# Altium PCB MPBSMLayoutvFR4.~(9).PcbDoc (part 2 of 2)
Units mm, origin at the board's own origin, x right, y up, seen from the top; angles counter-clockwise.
Board outline 131.7 x 110.39 mm, 4 copper layers (Top Layer, Power, GroundPlane, Bottom Layer), stack 2.286 mm thick; 156 components, 77 nets, 429 pads, 117 vias.
Unrouted connection lines stored in the file: 44.

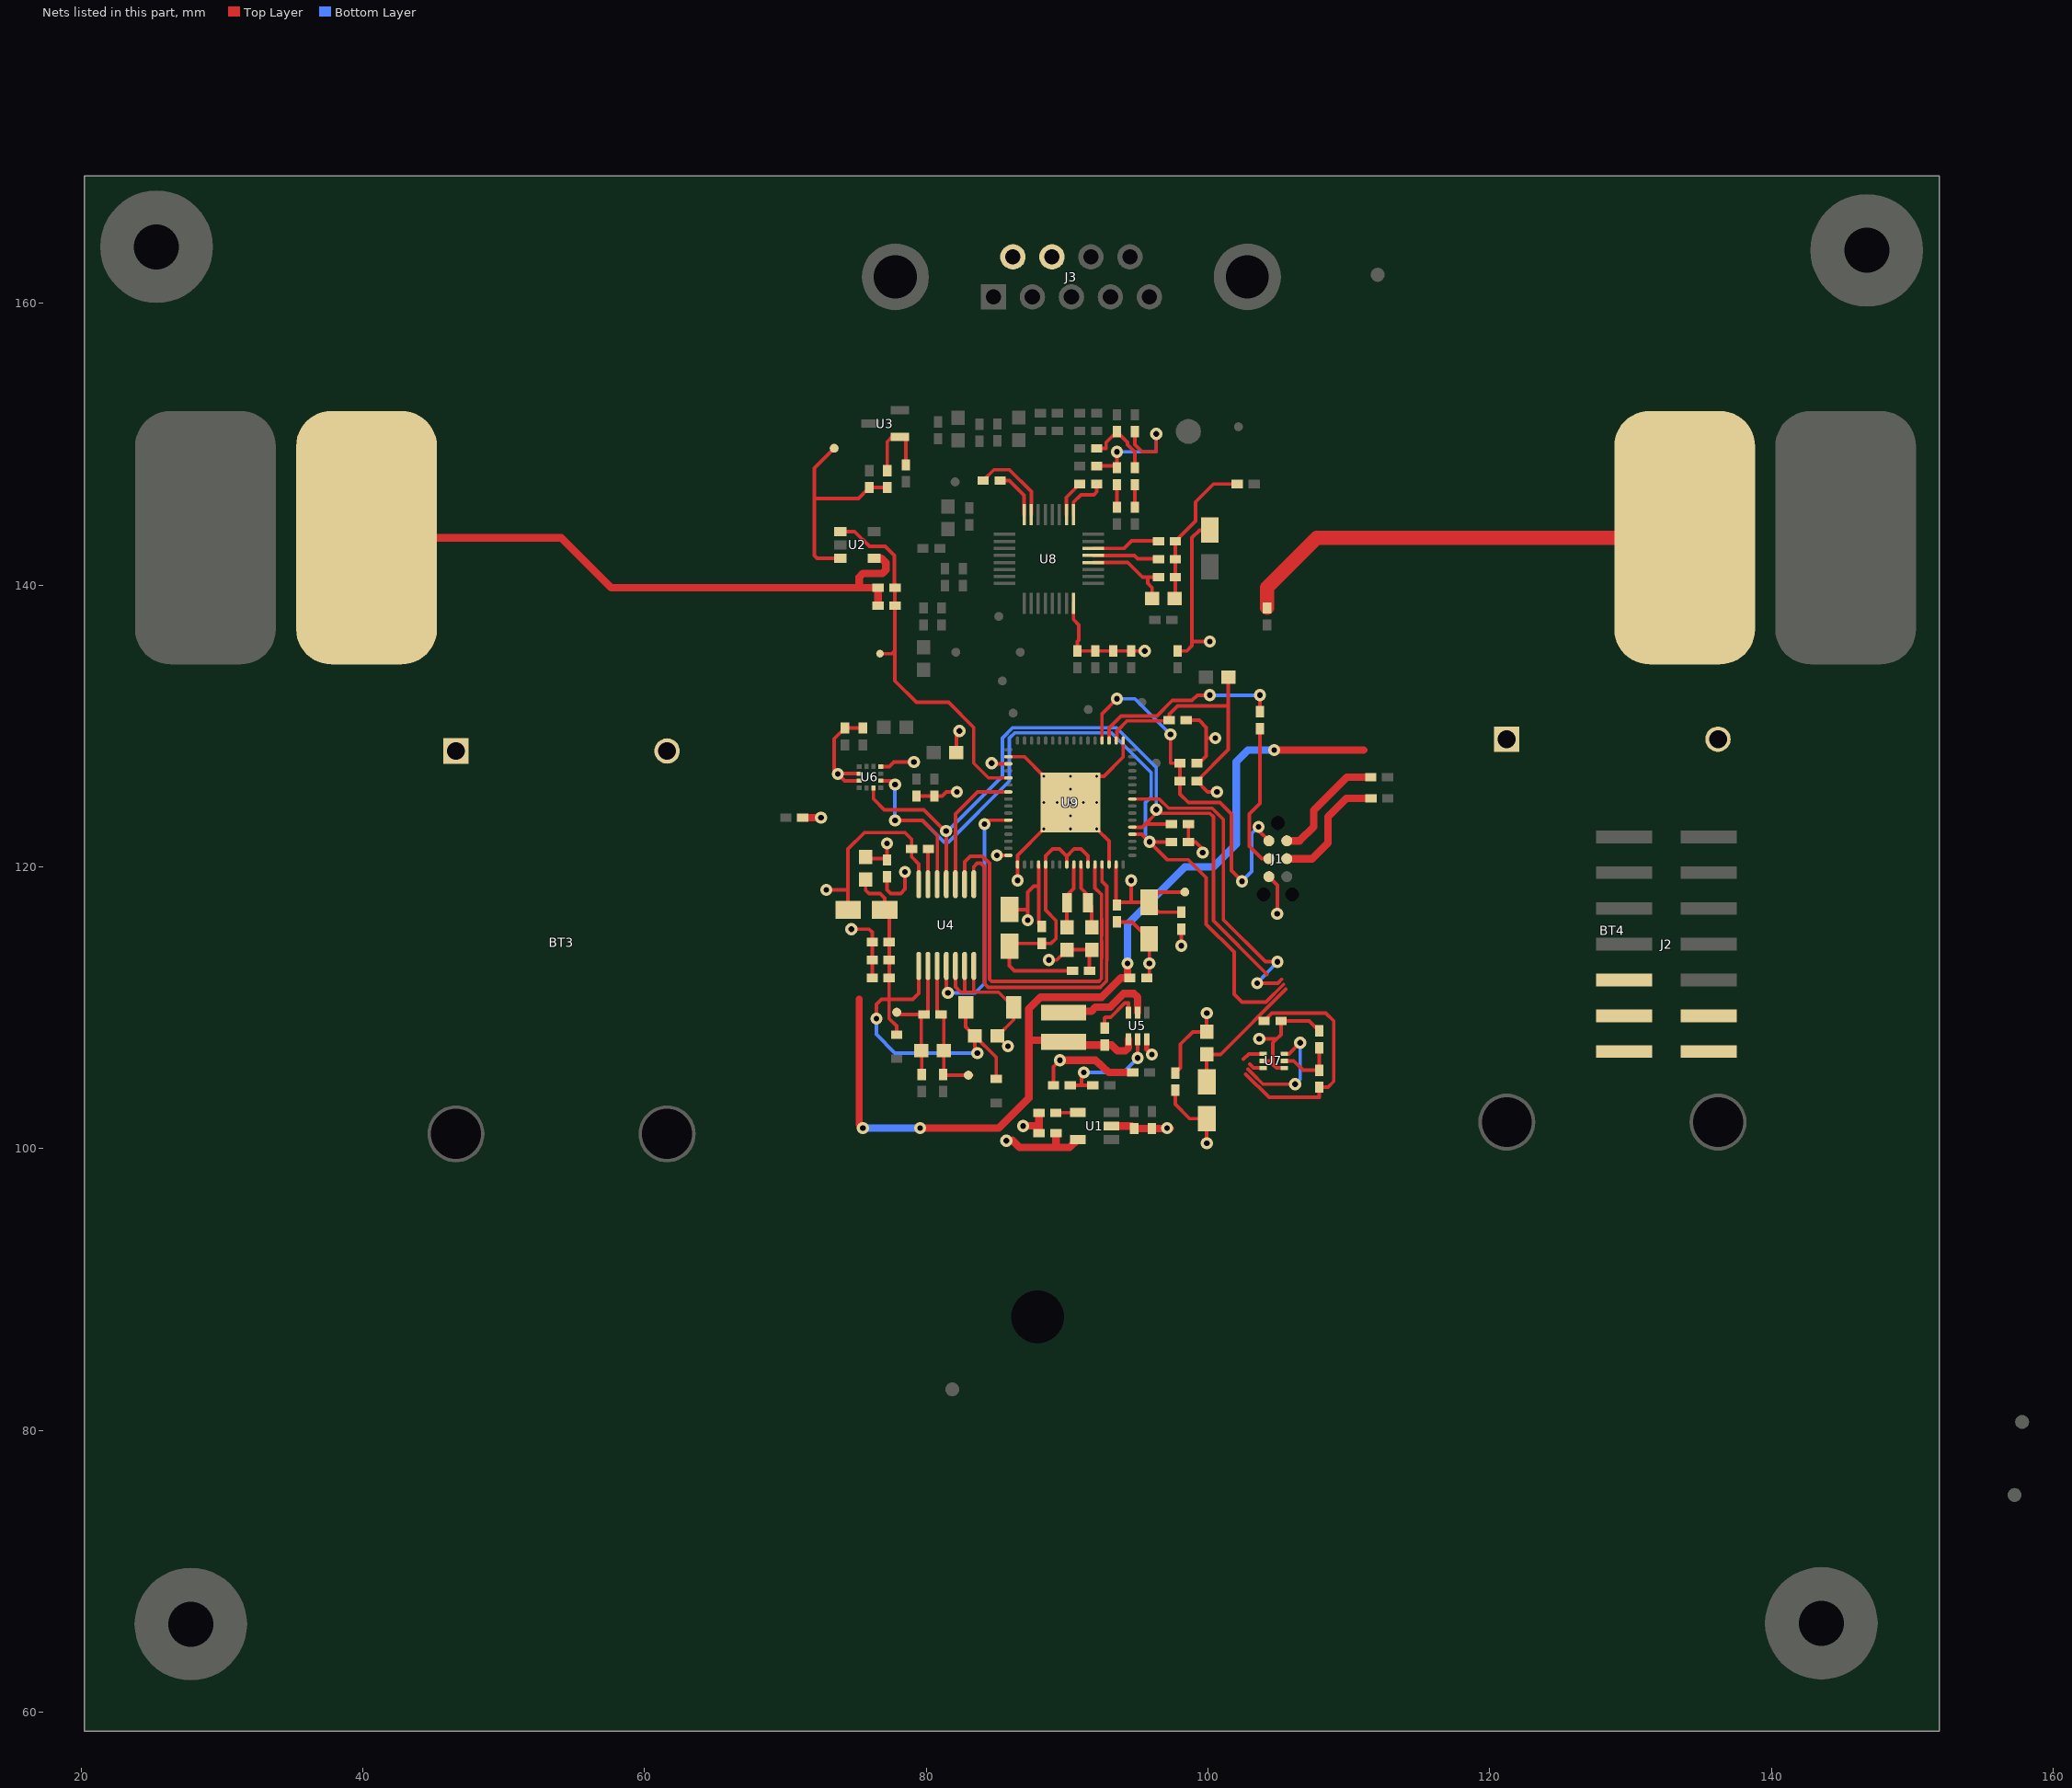
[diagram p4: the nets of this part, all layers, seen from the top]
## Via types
v1: diameter 0.864, hole 0.406, Top Layer to Bottom Layer, 104 vias
v2: diameter 0.5, hole 0.2, Top Layer to Bottom Layer, 13 vias

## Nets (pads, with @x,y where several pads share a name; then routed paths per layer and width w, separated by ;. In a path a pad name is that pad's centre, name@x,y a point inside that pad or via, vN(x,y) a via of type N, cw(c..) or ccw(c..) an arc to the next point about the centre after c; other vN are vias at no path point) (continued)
BOOST_INPUT: BT3.1 BT4.1 C34.1 L7.1 R16.1 U5.1 | length 73.3
  Top Layer w0.254: L7.1@89.739,107.681 L7.1@89.748,107.672 ; v1(94.285,113.132) v1@94.447,112.97
  Top Layer w0.5: 75.235,110.592 75.235,101.702 v1(75.489,101.448)
  Top Layer w0.54: v1(79.553,101.448) 85.141,101.448 87.274,103.581 87.274,109.906 88.113,110.744 92.456,110.744 93.828,112.116 C34.1@94.447,112.116 ; 87.274,107.696 L7.1@89.739,107.681 ; L7.1@89.959,107.35 R16.1@92.659,107.35 93.145,107.35 93.561,106.934 94.132,106.934 94.346,107.148 U5.1@94.346,107.762 ; C34.1@94.285,112.278 v1(94.285,113.132) ; v1(104.699,128.287) 111.048,128.287
  Bottom Layer w0.54: v1(75.489,101.448) v1(79.553,101.448) ; v1(94.285,113.132) 94.285,115.926 98.349,119.99 100.381,119.99 101.997,121.606 101.997,127.448 102.836,128.287 v1(104.699,128.287)
DVCC: 1.1 C1.1 C5.1 C6.1 C10.1 C14.1 C18.1 L1.1 L2.1 L3.1 L5.1 R1.1 R6.2 R31.1 R32.1 U1.5 U9.18 U9.35 U9.48 U9.63 | length 53
  Top Layer w0.254: L1.1@75.489,120.59 77.067,120.59 C10.1@77.091,120.613 ; C10.1@77.216,120.488 v1(77.216,121.666) ; L3.1@82.131,128.118 82.131,129.426 v1(82.347,129.642) ; v1@84.677,127.312 U9.35@85.821,127.312 ; v1(85.003,120.812) U9.48@85.821,120.812 ; U9.63@93.472,120.162 93.472,117.339 C6.1@93.523,117.288 ; U9.18@93.472,128.962 93.518,129.008 93.518,129.637 94.237,130.356 97.193,130.356 C18.1@97.241,130.404 97.241,130.82 97.841,131.42 101.397,131.42 ; C6.1@93.715,117.48 C1.1@95.809,117.48 ; 94.542,117.483 v1(94.542,119.027) ; C14.1@97.665,105.35 98.044,105.728 98.044,107.414 98.915,108.286 L2.1@99.906,108.286 v1(99.906,109.621) ; R1.1@98.095,116.78 96.509,116.78 C1.1@95.809,117.48 ; 1.1@98.349,118.212 96.541,118.212 C1.1@95.809,117.48 ; R32.1@98.603,123.038 R31.1@98.603,121.768 99.111,121.768 99.619,121.26 v1(99.619,121.006) ; v1(100.635,125.324) 99.965,125.324 R6.2@99.203,126.086 101.435,128.318 L5.1@101.435,133.452
  Top Layer w0.54: v1(85.674,100.559) v1@86.081,100.559 ; 86.106,100.584 86.614,100.076 89.2,100.076 ; C5.1@89.2,101.092 89.2,100.076 ; U1.5@90.748,100.65 90.174,100.076 89.2,100.076
  other v1: 84.633,127.356
EL_GSR1: C26.2 J3.7 R10.1 TP2.1 U2.4 | length 43.3
  Top Layer w0.254: U2.4@76.297,141.9 76.809,141.9
  Top Layer w0.54: TP2.1@40.259,143.358 54.077,143.358 57.633,139.802 R10.1@76.575,139.802 C26.2@76.575,138.532 ; 75.235,139.852 75.235,140.564 75.489,140.818 76.875,140.818 77.129,141.072 77.129,141.58 76.809,141.9
EL_GSR2: J3.6 R9.2 TP1.1 | length 32.6
  Top Layer w1: R9.2@104.191,138.37 104.191,139.827 107.721,143.358 TP1.1@133.833,143.358
GND: BT3.2 BT4.2 C1.2 C3.2 C4.2 C5.2 C6.2 C8.2 C9.2 C10.2 C11.2 C12.2 C13.2 C14.2 C15.2 C16.2 C17.2 C18.2 C19.2 C20.2 C21.2 C25.2 C27.2 C28.2 C29.1 C32.2 C33.2 C34.2 C35.2 C36.2 C37.2 C38.2 C41.2 C42.2 C58.2 C59.2 J1.6 J2.6 R2.1 R3.1 R17.1 U1.2 U4.5 U4.6 U4.7 U4.14 U5.3 U6.4 U6.8 U6.9 U7.2 U7.4 U8.24 U9.17 U9.34 U9.49 U9.62 U9.65 | length 145.9
  Top Layer w0.254: v1(72.898,118.364) 74.443,118.364 ; C9.2@74.443,116.942 74.443,118.364 ; v1(74.676,115.57) 75.946,115.57 76.159,115.357 C27.2@76.159,114.656 C11.2@76.159,113.386 C28.2@76.159,112.116 ; U6.9@75.222,126.111 74.194,126.111 v1(73.711,126.594) ; U6.8@75.222,126.611 73.728,126.611 v1(73.711,126.594) ; C37.2@75.489,129.847 C16.2@74.219,129.847 73.457,129.085 73.457,126.848 v1(73.711,126.594) ; U6.4@76.772,127.111 77.376,127.111 77.698,127.433 v1(79.117,127.433) ; C10.2@77.216,119.288 77.216,118.364 77.47,118.11 78.174,118.11 78.486,118.422 v1(78.486,119.634) ; C36.2@79.299,125.024 C17.2@80.569,125.024 81.124,125.024 81.424,125.324 v1(82.169,125.324) ; U4.14@79.464,118.764 79.464,120.193 78.953,120.704 C29.1@78.953,121.26 78.953,121.961 78.486,122.428 75.611,122.428 74.443,121.26 74.443,118.364 ; U4.5@82.064,112.964 82.064,111.484 82.448,111.1 83.363,111.1 ; 82.714,111.137 U4.6@82.714,112.964 ; U4.7@83.364,112.964 83.363,111.1 ; v1(85.797,107.266) 85.772,107.266 C33.2@85.047,107.991 86.201,109.145 C32.2@86.201,110.023 85.124,111.1 83.363,111.1 ; U9.34@85.821,127.812 86.971,127.812 v2(88.346,126.437) v2(90.221,124.562) ; v1(86.47,119.033) U9.49@86.47,120.162 86.47,120.811 v2(88.346,122.687) v2(90.221,124.562) ; v1(86.868,101.6) v1@86.881,101.613 ; v1(88.697,113.386) 89.243,113.386 89.967,114.11 C58.2@91.745,114.11 ; R17.1@89.021,104.496 89.021,105.812 v1(89.483,106.274) ; U8.24@90.447,138.704 90.447,137.544 90.829,137.162 90.829,136.099 90.729,135.999 C42.2@90.729,135.322 C41.2@91.999,135.322 C19.2@93.269,135.322 C20.2@94.539,135.322 v1@95.444,135.322 ; R2.1@91.583,112.624 C58.2@91.583,113.948 ; U9.62@92.971,120.162 92.971,121.811 v2(92.096,122.687) v2(90.221,124.562) ; C6.2@93.523,115.888 C6.2@93.523,116.088 94.601,116.088 C1.2@95.809,114.88 95.827,114.861 v1(95.827,113.132) 95.827,112.296 C34.2@95.647,112.116 C34.2@95.809,111.954 ; U9.17@93.972,128.962 93.972,127.805 92.604,126.437 v2(92.096,126.437) v2(90.221,124.562) ; C3.2@94.574,101.6 C3.2@94.747,101.428 ; v1(97.079,101.448) 97.079,101.194 v1@97.313,101.428 ; C14.2@97.665,104.15 97.665,103.147 98.691,102.122 C12.2@99.906,102.122 v1(99.906,100.374) ; C21.2@97.841,135.322 98.492,135.322 98.857,135.687 98.857,143.358 99.395,143.896 C15.2@100.127,143.896 C15.2@100.127,144.374 ; C18.2@98.441,130.404 99.365,130.404 99.873,129.896 99.873,129.134 ; 98.857,135.992 v1(100.127,135.992) ; C25.2@99.203,127.356 99.365,127.356 99.873,127.864 99.873,129.134 ; v1(100.508,129.134) 99.873,129.134 ; v1(103.627,107.783) 104.872,107.783 ; U7.2@103.906,106.221 104.576,106.221 ; J1.6@104.318,119.304 104.927,118.694 104.927,116.688 v1(104.902,116.662) ; U7.4@105.406,105.721 104.851,105.721 104.601,105.971 104.601,107.512 104.872,107.783 ; C38.2@107.884,108.352 107.168,109.068 C13.2@105.182,109.068 105.182,108.093 104.872,107.783
  Top Layer w0.354: U5.3@95.646,107.762 95.646,107.046 v1(96.012,106.68)
  Top Layer w0.54: R3.1@71.221,123.489 v1(72.524,123.489) ; v1@86.881,101.613 88,101.613 ; C5.2@88,101.092 88,101.613 ; C8.2@88,102.54 88,101.613 ; v1(89.483,106.274) 90.799,106.274 91.999,106.274 92.964,105.41 C35.2@94.7,105.41 ; U1.2@93.148,101.6 C3.2@94.574,101.6 ; C3.2@94.747,101.428 C4.2@96.017,101.428 v1@97.313,101.428
  other v1: 95.504,135.322
  other v2: 90.221,122.687 90.221,123.624 88.346,124.562 89.283,124.562 91.158,124.562 92.096,124.562 90.221,125.499 90.221,126.437
GSR_ANALOG_OUTPUT: 2.1 C26.1 R10.2 U2.1 U9.37 | length 26.9
  Top Layer w0.254: U2.1@73.897,143.8 74.903,143.8 75.955,142.748 77.072,142.748 77.733,142.088 77.733,140.14 77.775,140.098 R10.2@77.775,139.802 C26.1@77.775,138.532 77.775,135.23 ; 2.1@76.708,135.128 77.673,135.128 ; 77.673,135.23 77.775,135.23 ; U9.37@85.821,126.312 84.407,126.312 83.363,127.356 83.363,129.896 81.585,131.674 79.299,131.674 77.775,133.198 77.775,135.23
JTAG_TCK: J1.4 J2.4 R7.1 | length 10.4
  Top Layer w0.254: R7.1@103.683,129.804 103.683,124.511 102.921,123.749 102.921,121.463 103.81,120.574 J1.4@104.318,120.574
JTAG_TDO/TDI: C25.1 J1.2 J2.2 R6.1 U9.20 | length 28.1
  Top Layer w0.254: U9.20@92.471,128.962 92.471,130.876 v1(93.523,131.928) ; v1(97.333,129.388) 97.333,127.356 C25.1@98.003,127.356 R6.1@98.003,126.086 98.003,125.162 98.603,124.562 100.829,124.562 101.651,123.74 101.651,119.736 v1(102.413,118.974) ; v1(103.581,122.843) 103.581,122.58 J1.2@104.318,121.844
  Bottom Layer w0.254: v1(93.523,131.928) 94.793,131.928 v1(97.333,129.388) ; v1(102.413,118.974) 103.099,119.659 103.099,122.36 v1(103.581,122.843)
JTAG_TEST/SBWTCK: R7.2 U9.19 | length 13.7
  Top Layer w0.254: U9.19@92.971,128.962 92.971,129.852 93.829,130.71 96.369,130.71 97.46,131.801 98.855,131.801 99.236,132.182 v1(100.127,132.182) ; R7.2@103.683,131.004 v1(103.683,132.182)
  Bottom Layer w0.254: v1(100.127,132.182) v1(103.683,132.182)
JTAG_VCC_TARGET_IN: J1.3 J2.3 R5.1 | length 8.8
  Top Layer w0.54: J1.3@105.588,120.574 107.391,120.574 108.509,121.691 108.509,122.707 108.509,123.546 109.824,124.861 R5.1@111.56,124.861
JTAG_VCC_TOOL_OUT: J1.1 J2.1 R4.1 | length 8.5
  Top Layer w0.54: J1.1@105.588,121.844 106.502,121.844 107.493,122.834 107.493,124.003 109.855,126.365 R4.1@111.541,126.365
MSP_AVCC: C2.1 C7.1 R1.2 U9.52 | length 9.3
  Top Layer w0.254: C2.1@86.222,116.972 87.203,116.972 ; v1(87.203,116.21) 87.203,116.972 ; C7.1@87.97,115.982 87.97,118.618 ; U9.52@87.97,120.162 87.97,118.618 ; v1(98.095,114.402) R1.2@98.095,115.58 ; 87.203,116.972 87.203,118.191 87.63,118.618 87.97,118.618
MSP_AVSS: C2.2 C7.2 R2.2 U9.53 U9.56 U9.59 | length 20.5
  Top Layer w0.254: C2.2@85.903,114.372 85.903,112.979 86.258,112.624 R2.2@90.383,112.624 ; C2.2@86.095,114.564 C7.2@88.189,114.564 88.859,114.564 89.205,114.91 89.205,116.18 88.47,116.914 U9.53@88.47,120.162 88.47,120.779 88.951,121.26 89.459,121.26 89.963,120.756 ; U9.56@89.971,120.162 89.971,120.756 90.475,121.26 90.983,121.26 91.471,120.771 U9.59@91.471,120.162
MSP_LFXIN: C59.1 U9.57 Y1.1 | length 4.1
  Top Layer w0.254: C59.1@89.967,115.71 89.967,117.438 Y1.1@89.979,117.45 ; Y1.1@89.979,117.97 90.471,118.462 U9.57@90.471,120.162
MSP_LFXOUT: C58.1 U9.58 Y1.2 | length 4.3
  Top Layer w0.254: U9.58@90.971,120.162 90.971,118.477 Y1.2@91.479,117.97 ; Y1.2@91.479,117.45 91.745,117.184 C58.1@91.745,115.71
MSP_P1.0_INT: U4.10 U9.39 | length 9.4
  Top Layer w0.254: U4.10@82.064,118.764 82.064,123.749 ; 82.079,123.749 83.642,125.312 U9.39@85.821,125.312
MSP_P2.7_INT: U7.3 U9.9 | length 24.2
  Top Layer w0.254: U9.9@94.621,124.812 96.544,124.812 97.202,124.154 100.281,124.154 101.089,123.346 101.089,116.234 104.064,113.259 v1(104.927,113.259) ; 102.968,105.989 103.236,105.721 U7.3@103.906,105.721 ; v1@103.488,111.743 104.949,111.743 105.217,112.011
  Bottom Layer w0.254: v1(103.48,111.735) v1(104.927,113.259)
MSP_P4.0_INT: U4.9 U9.60 | length 28.4
  Top Layer w0.254: U4.9@82.714,118.764 82.714,120.356 83.109,120.752 83.976,120.752 84.479,120.248 84.479,112.016 84.633,111.862 92.253,111.862 92.437,112.046 92.437,113.506 92.447,113.516 92.447,114.704 92.437,114.713 92.437,115.106 92.447,115.116 92.447,116.304 92.437,116.313 92.437,118.027 91.971,118.493 U9.60@91.971,120.162
MSP_P4.1_INT: U4.8 U9.61 | length 27.8
  Top Layer w0.254: U4.8@83.364,118.764 83.364,119.99 83.617,120.244 83.871,120.244 84.125,119.99 84.125,111.718 84.389,111.454 92.353,111.454 ; 92.353,111.461 92.791,111.9 92.791,113.36 92.801,113.369 92.801,118.612 92.471,118.942 U9.61@92.471,120.162
MSP_P9.3_OUT: U4.4 U9.43 | length 18
  Top Layer w0.254: U4.4@81.414,112.964 81.414,111.169 v1(81.534,111.049) ; v1(84.125,123.038) 84.399,123.312 U9.43@85.821,123.312
  Bottom Layer w0.254: v1(81.534,111.049) 83.456,111.049 84.125,111.718 v1(84.125,123.038)
MSP_UCB0SCL_TMP103_SCL_RF430CL330HCPW_SCL: R32.2 U4.11 U6.12 U7.1 U9.5 | length 56.8
  Top Layer w0.254: U6.12@76.247,125.586 76.247,124.82 77.013,124.054 79.807,124.054 v1@81.363,122.497 ; U4.11@81.414,118.764 v1@81.414,122.447 ; U9.5@94.621,122.812 95.329,122.812 95.555,123.038 ; v1(96.317,124.054) v1@96.317,123.8 ; R32.2@97.241,123.038 95.555,123.038 ; 102.518,106.343 102.895,106.721 U7.1@103.906,106.721 ; 104.171,112.365 103.988,112.547 100.381,116.18 100.381,123.546 100.127,123.8 v1@96.317,123.8 ; 95.555,123.038 v1@96.317,123.8
  Bottom Layer w0.254: v1(81.405,122.539) 81.414,122.531 81.414,122.447 85.395,126.428 85.395,129.134 86.127,129.866 93.492,129.866 96.317,127.042 v1(96.317,124.054)
MSP_UCB0SDA_TMP103_SDA_RF430CL330HCPW_SDA: R31.2 U4.12 U6.2 U7.6 U9.4 | length 70.6
  Top Layer w0.254: U6.2@76.772,126.111 77.496,126.111 v1(77.775,125.832) ; v1(77.775,123.292) 79.721,123.292 80.78,122.233 80.78,118.78 U4.12@80.764,118.764 ; U9.4@94.621,122.312 95.301,122.312 v1(95.845,121.768) ; R31.2@97.403,121.768 v1(95.845,121.768) ; 102.821,105.635 103.125,105.332 103.132,105.332 103.894,104.57 v1(106.18,104.57) ; 105.363,111.657 104.095,110.388 102.413,110.388 101.841,110.96 101.841,113.957 99.873,115.926 99.873,119.228 98.603,120.498 97.115,120.498 v1(95.845,121.768) ; U7.6@105.406,106.721 105.74,106.721 v1(106.536,107.516)
  Bottom Layer w0.254: v1(77.775,125.832) v1(77.775,123.292) 79.721,123.292 81.245,121.768 81.585,121.768 85.903,126.086 85.903,129.134 86.281,129.512 93.144,129.512 95.963,126.694 95.963,124.97 95.555,124.562 95.555,122.058 v1(95.845,121.768) ; v1(106.18,104.57) 106.536,104.925 v1(106.536,107.516)
Net3_1: 3.1 R11.1 R12.2 U2.3 | length 15.6
  Top Layer w0.254: 72.049,146.152 75.186,146.152 R12.2@75.951,146.917 R11.1@77.221,146.917 ; 3.1@73.457,149.708 72.049,148.3 72.049,142.088 72.237,141.9 U2.3@73.897,141.9
Net4_1: 4.1 C30.1 C31.1 R13.1 U4.2 | length 9.9
  Top Layer w0.254: 4.1@77.897,109.676 78.059,109.515 C31.1@79.837,109.515 ; R13.1@79.675,105.255 79.675,106.903 C30.1@79.637,106.941 79.637,109.315 C31.1@79.837,109.515 ; U4.2@80.114,112.964 80.114,109.791 C31.1@79.837,109.515
Net5_1: 5.1 C30.2 C31.2 R14.1 U4.3 | length 9.9
  Top Layer w0.254: U4.3@80.764,112.964 80.764,109.788 C31.2@81.037,109.515 81.237,109.315 C30.2@81.237,106.941 81.237,105.293 81.334,105.197 5.1@83.231,105.197
NetC8_1: C8.1 U1.4 | length 1.6
  Top Layer w0.254: C8.1@89.195,102.54 89.205,102.55 U1.4@90.748,102.55
NetC29_2: C29.2 U4.13 | length 2.5
  Top Layer w0.254: U4.13@80.114,118.764 80.114,121.22 C29.2@80.153,121.26
NetC38_1: C38.1 R18.1 U7.5 | length 4.3
  Top Layer w0.254: U7.5@105.406,106.221 106.078,106.221 106.742,105.558 R18.1@107.884,105.558 C38.1@107.884,107.152
NetC43_1: C43.1 R19.2 R20.2 R21.2 R22.1 | length 10.9
  Top Layer w0.254: C43.1@97.679,139.094 R20.2@97.679,140.564 R21.2@97.679,141.834 97.679,141.876 R19.2@97.679,143.104 99.111,144.536 99.111,145.898 99.831,146.618 100.381,147.168 R22.1@102.067,147.168
NetC43_2: C43.2 R20.1 U8.28 | length 6.7
  Top Layer w0.254: U8.28@91.846,141.603 94.299,141.603 95.339,140.564 95.707,140.564 ; C43.2@96.025,139.04 96.025,139.818 95.707,140.135 95.707,140.564 ; R20.1@96.479,140.564 95.707,140.564
NetC45_1: C45.1 U8.2 | length 2.6
  Top Layer w0.254: U8.2@89.947,145.003 89.947,146.224 C45.1@90.891,147.168
NetC45_2: C45.2 U8.1 | length 3.4
  Top Layer w0.254: U8.1@90.447,145.003 90.447,145.87 90.983,146.406 91.885,146.406 92.091,146.612 C45.2@92.091,147.168
NetC46_2: C46.2 C48.2 C49.2 | length 10.4
  Top Layer w0.254: C46.2@92.091,148.45 C49.2@93.394,148.45 ; C49.2@93.523,148.322 v1(93.523,149.454) ; C48.2@94.793,150.886 94.798,150.88 94.798,149.967 95.312,149.454 96.317,149.454 v1(96.317,150.724)
  Bottom Layer w0.254: v1(93.523,149.454) 96.317,149.454 v1(96.317,150.724)
NetC47_1: C47.1 U8.8 | length 3.5
  Top Layer w0.254: C47.1@85.233,147.422 85.903,147.422 86.947,146.378 U8.8@86.947,145.003
NetC47_2: C47.2 U8.7 | length 6
  Top Layer w0.254: C47.2@84.033,147.422 84.795,148.184 85.903,148.184 87.447,146.64 U8.7@87.447,145.003
NetC49_1: C49.1 R26.1 | length 1.6
  Top Layer w0.254: R26.1@93.523,145.528 C49.1@93.523,147.122
NetC52_2: C52.2 C53.2 C54.2 | length 5.3
  Top Layer w0.254: C54.2@92.091,149.708 92.761,149.708 92.761,150.124 C52.2@93.523,150.886 94.285,150.124 94.285,149.962 94.793,149.454 C53.2@94.793,148.322
NetC53_1: C53.1 R27.1 | length 1.6
  Top Layer w0.254: R27.1@94.793,145.528 C53.1@94.793,147.122
NetL7_2: L7.2 U5.5 | length 5.5
  Top Layer w0.254: 93.066,110.033 93.066,110.084
  Top Layer w0.54: L7.2@91.186,109.752 91.718,109.752 91.999,110.033 93.066,110.033 ; 93.066,110.084 93.646,110.664 93.98,110.998 94.742,110.998 94.996,110.744 U5.5@94.996,109.662
NetR8_1: R8.1 R11.2 U3.1 | length 5.5
  Top Layer w0.254: R11.2@77.221,148.117 77.221,150.17 77.587,150.536 78.537,150.536 R8.1@78.537,148.53
NetR15_1: R15.1 R17.2 U5.2 | length 8.1
  Top Layer w0.254: R17.2@90.221,104.496 91.018,104.496 ; v1(91.186,105.41) 91.018,105.242 91.018,104.496 ; R15.1@91.815,104.496 91.018,104.496 ; v1(94.996,106.426) U5.2@94.996,107.762
  Bottom Layer w0.254: v1(91.186,105.41) 93.98,105.41 v1(94.996,106.426)
NetR16_2: R16.2 U5.6 | length 3.5
  Top Layer w0.254: R16.2@92.659,108.55 92.659,109.271 92.71,109.322 93.091,109.322 94.096,110.327 94.336,110.327 94.336,109.672 U5.6@94.346,109.662
NetR19_1: R19.1 U8.30 | length 4.9
  Top Layer w0.254: U8.30@91.846,142.603 94.038,142.603 94.581,143.146 R19.1@96.479,143.146
NetR21_1: R21.1 U8.29 | length 4.7
  Top Layer w0.254: U8.29@91.846,142.103 94.777,142.103 95.005,141.876 R21.1@96.479,141.876
RF430_DVCC: C9.1 C11.1 C27.1 C28.1 C32.1 C33.1 D1.1 D2.1 L1.2 U4.1 | length 34
  Top Layer w0.254: 75.692,118.512 75.692,118.338 75.938,118.092 76.726,118.092 77.043,117.775 C9.1@77.043,116.942 C9.1@77.267,117.166 ; v1(76.454,109.22) 76.454,110.236 76.81,110.592 77.353,110.592 ; C28.1@77.359,112.116 C11.1@77.359,113.386 C27.1@77.359,114.656 C9.1@77.359,116.626 ; C28.1@77.451,112.024 77.353,111.926 77.353,110.592 ; D1.1@77.897,108.079 77.897,108.691 77.353,109.235 77.353,110.592 ; U4.1@79.464,112.964 79.464,111.01 79.045,110.592 77.353,110.592 ; C32.1@82.801,110.023 82.801,108.637 C33.1@83.447,107.991 ; v1(83.617,106.782) 83.447,106.951 C33.1@83.447,107.991 ; D2.1@84.963,104.989 84.963,106.475 C33.1@83.447,107.991
  Bottom Layer w0.254: v1(76.454,109.22) 76.454,108.102 77.775,106.782 v1(83.617,106.782)
TMP_DVCC: C12.1 C13.1 L2.2 R18.2 | length 27
  Top Layer w0.254: C12.1@99.906,104.722 L2.2@99.906,106.686 100.893,106.686 105.51,111.303 ; 102.675,105.281 104.326,103.63 107.884,103.63 R18.2@107.884,104.358 108.508,104.358 108.919,104.768 108.919,109.049 108.35,109.618 104.532,109.618 C13.1@103.982,109.068
pads on no net: BT3.3 BT3.4 BT4.3 BT4.4 FID1.1 FID2.1 FID3.1 H1.0 H2.0 H3.0 H4.0 H5.1 H6.1 H7.1 H8.1 H9.0 H10.0 H11.0 H12.0 J1.5 J1.MH1 J1.MH2 J1.MH3 J2.5 J2.7 J2.8 J2.9 J2.10 J2.11 J2.12 J2.13 J2.14 J3.3 J3.5 J3.8 J3.9 U3.3 U6.10 U8.17 U9.1 U9.2 U9.3 U9.6 U9.7 U9.8 U9.10 U9.11 U9.12 U9.13 U9.15 U9.21 U9.22 U9.23 U9.24 U9.36 U9.40 U9.41 U9.42 U9.44 U9.45 U9.46 U9.47 U9.50 U9.51 U9.54 U9.55 U9.64
copper on no net: | length 0.5
  Top Layer w0.254: 104.648,124.206 v1(104.648,124.714)

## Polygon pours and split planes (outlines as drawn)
ADS_AVSS on GroundPlane (split plane): 151.407,158.471 151.407,128.806 102.288,128.806 102.288,137.008 102.278,137.057 102.25,137.099 102.208,137.127 102.159,137.137 99.111,137.137 99.061,137.127 99.019,137.099 98.991,137.057 98.981,137.008 98.981,135.765 96.649,135.765 96.649,136.398 96.64,136.448 96.612,136.49 96.57,136.518 96.52,136.527 89.581,136.527 89.566,136.524 89.55,136.524 89.541,136.52 89.531,136.518 89.518,136.509 89.504,136.503 77.834,127.993 20.729,128.018 20.729,168.527 151.407,168.527
GND on GroundPlane (split plane): 102.029,128.676 102.039,128.627 102.067,128.585 102.109,128.557 102.159,128.547 151.407,128.547 151.407,59.159 20.729,59.159 20.729,127.759 77.877,127.734 77.926,127.744 77.968,127.772 77.971,127.776 77.987,127.784 89.623,136.269 96.391,136.269 96.391,135.636 96.4,135.586 96.428,135.544 96.47,135.516 96.52,135.507 99.111,135.507 99.16,135.516 99.202,135.544 99.23,135.586 99.24,135.636 99.24,136.878 102.029,136.878
DVCC on Power (split plane): 102.537,142.288 102.537,131.727 101.902,131.092 78.794,131.092 78.158,131.727 78.158,133.144 79.352,134.338 93.269,134.338 93.318,134.348 93.36,134.376 98.44,139.456 98.468,139.498 98.478,139.548 98.478,142.796 98.887,143.205 101.621,143.205
DVCC on Power (split plane): 87.714,117.065 88.059,116.61 88.059,112.624 88.069,112.574 88.097,112.532 88.139,112.504 88.189,112.494 96.155,112.494 96.204,112.504 96.246,112.532 97.17,113.456 97.198,113.498 97.208,113.548 97.208,115.796 98.971,115.796 98.971,115.57 98.971,113.937 98.511,113.477 97.234,112.2 96.771,111.737 86.93,111.737 86.286,112.41 86.286,116.653 86.701,117.089
DVCC on Power (split plane): 90.853,154.534 90.812,146.998 82.093,147.043 82.068,147.038 82.044,147.033 82.043,147.033 82.023,147.019 82.002,147.006 82.002,147.005 82.001,147.005 81.987,146.984 81.973,146.964 81.973,146.963 81.968,146.939 81.963,146.914 81.963,143.104 81.973,143.054 82.001,143.012 82.043,142.984 82.093,142.974 86.789,142.974 86.789,141.201 83.617,141.201 83.567,141.191 83.525,141.163 83.497,141.121 83.487,141.072 83.487,135.359 77.345,135.359 77.345,139.09 77.336,139.14 77.308,139.182 75.11,141.379 75.11,145.59 78.127,148.607 79.266,148.607 79.291,148.612 79.315,148.616 79.315,148.617 79.316,148.617 79.336,148.631 79.357,148.644 79.357,148.645 79.358,148.645 79.371,148.665 79.385,148.686 79.386,148.687 79.39,148.711 79.395,148.736 79.428,154.658 90.853,154.658
DVCC on Power (split plane): 151.407,158.471 151.407,59.159 20.729,59.159 20.729,168.527 151.407,168.527

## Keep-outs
Keep-Out Layer:
  text ".Layer_Name" at 157.226,108.306 h1.52

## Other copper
Top Layer:
  text ".Layer_Name" at 157.226,156.566 h1.52
Bottom Layer:
  text ".Layer_Name" at 157.226,154.026 h1.52
  text "SVN:" at 49.847,114.91 h1.52 r90
  text ".VersionControl_RevNumber" at 49.847,107.823 h1.52 r90
  text "UL94V-0" at 55.88,69.774 h1.52 r90
Power (plane layer: these items are gaps in the copper):
  rectangle: 74.981,69.952 100.381,99.67
  lines w0.254: 99.101,115.57 99.101,115.926 ; 99.101,115.926 98.697,115.926 97.079,115.926 97.079,113.548 96.155,112.624 88.408,112.624 88.189,112.624 88.189,116.654 87.779,117.193 86.647,117.219 86.157,116.705 86.157,112.358 86.875,111.608 92.343,111.608 96.825,111.608 97.325,112.108 98.603,113.386 99.101,113.884 99.101,115.926 ; 74.981,141.326 77.216,139.09 77.216,135.23 81.389,135.23 83.617,135.23 83.617,141.072 86.919,141.072 86.919,143.104 82.093,143.104 82.093,146.914 90.941,146.868 90.983,154.534 90.983,154.788 79.299,154.788 79.266,148.736 78.073,148.736 74.981,145.644 74.981,141.326 ; 78.029,131.674 78.029,133.198 79.299,134.468 93.269,134.468 98.349,139.548 98.349,142.85 98.833,143.334 101.674,143.334 102.667,142.342 102.667,131.674 101.956,130.962 78.74,130.962 78.029,131.674
GroundPlane (plane layer: these items are gaps in the copper):
  rectangle: 74.981,69.952 100.381,99.67
  lines w0.254: 20.244,127.889 77.877,127.864 ; 77.911,127.888 89.581,136.398 96.52,136.398 96.52,135.636 99.111,135.636 99.111,137.008 102.159,137.008 102.159,128.676 151.917,128.676

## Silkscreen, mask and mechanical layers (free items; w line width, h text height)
Top Overlay:
  region: 96.52,77.724 96.52,85.344 93.98,85.344 93.98,77.724
  lines w1: 74.066,70.891 101.194,70.891 101.194,98.222 74.066,98.222 74.066,70.891
  lines w2: 21.133,133.325 44.933,133.325 150.444,133.325 ; 49.124,60.96 49.124,132.918 49.124,167.716 ; 125.832,61.646 125.832,167.157
  text "GSR" at 130.251,153.289 h4
  text "ECG" at 141.63,153.238 h4
  text "ECG" at 24.892,152.806 h4
  text "GSR" at 37.541,152.756 h4
  text "GND" at 46.787,131.318 h1.02
  text "VCC" at 60.3,129.845 h1.02
  text ".Layer_Name" at 157.226,128.626 h1.52
  text "JTAG" at 106.934,126.009 h1.02
  text "BAT" at 110.744,122.987 h1.02
  text "VCC" at 62.179,121.361 h1.02
  text "GND" at 47.041,121.158 h1.02
  text "FOR DEMO PURPOSES ONLY" at 76.683,94.259 h1.02
  text "MPBSM" at 80.264,91.44 h1.02
  text "REV A" at 80.264,89.916 h1.02
  text "TI" at 92.354,87.884 h1.52
  text "©" at 94.996,87.63 h2.67
  text ".CopyrightYear" at 85.344,77.724 h1.52
  text "MADE IN U.S." at 78.994,75.438 h1.52
  text "NFC Antenna" at 80.747,68.504 h2
  text "-" at 51.105,67.666 h1.52 r90
  text "Place phone here" at 53.111,62.84 h10
Bottom Overlay:
  text ".Layer_Name" at 157.226,126.086 h1.52
Top Paste:
  text ".Layer_Name" at 157.226,123.546 h1.52
Bottom Paste:
  text ".Layer_Name" at 157.226,121.006 h1.52
Top Solder:
  text ".Layer_Name" at 157.226,118.466 h1.52
  text ".Layer_Name" at 157.226,115.926 h1.52
Bottom Solder:
  text ".Layer_Name" at 157.226,113.386 h1.52
Drill Guide:
  text ".Layer_Name" at 157.226,110.846 h1.52
M1 Board Outline:
  lines w0.254: 75.489,58.257 101.778,58.257
  text ".Layer_Name" at 157.226,151.486 h1.52
M2 Board Dimensions:
  rectangle: 17.577,32.982 20.752,36.157
  rectangle: 20.752,29.807 30.277,32.982
  lines w0.178: 17.577,32.982 42.977,32.982 ; 20.752,29.807 20.752,36.157 ; 23.927,29.807 23.927,36.157 ; 30.277,29.807 30.277,36.157 ; 36.627,29.807 36.627,36.157 ; 17.577,29.807 42.977,29.807 42.977,36.157 17.577,36.157 17.577,29.807
  text ".Layer_Name" at 18.034,37.338 h1.52
M3 3D STEP Top:
  text ".Layer_Name" at 157.226,148.946 h1.52
M4 3D STEP Bottom:
  text ".Layer_Name" at 157.226,146.406 h1.52
M5 Assembly Top:
  lines w0.254: 10.16,16.607 177.8,16.607 ; 10.16,21.772 177.851,21.772 ; 10.16,26.937 10.16,11.443 111.887,11.443 177.851,11.443 177.851,26.937 10.173,26.937 10.173,11.443 50.19,11.443 ; 72.771,11.443 72.771,26.937 ; 104.953,21.772 104.953,26.937 ; 126.289,21.772 126.289,26.937 ; 142.088,11.278 142.088,16.43
  text "COMPONENTS MARKED 'DNP' SHOULD NOT BE POPULATED." at 46.876,32.144 h1.52
  text "ASSEMBLY VARIANT:" at 46.863,29.21 h1.52
  text ".VariantName" at 73.177,29.21 h1.52
  text "PCB VIEWED FROM TOP SIDE" at 11.773,23.58 h1.52
  text "BOARD #:" at 74.676,23.58 h1.52
  text ".PRJ_Number" at 88.532,23.58 h1.52
  text "REV:" at 109.982,23.58 h1.52
  text ".PCB_Rev" at 117.386,23.58 h1.52
  text "SVN REV:" at 131.267,23.58 h1.52
  text ".VersionControl_RevNumber" at 144.12,23.58 h1.52
  text "IGNORE ->" at 11.773,18.428 h1.52
  text "PLOT NAME =" at 11.773,13.199 h1.52
  text ".plot_File_Name" at 32.233,13.199 h1.52
  text "GENERATED    :" at 74.727,13.199 h1.52
  text ".Print_Date" at 96.812,13.199 h1.52
  text ".Print_Time" at 115.329,13.199 h1.52
  text "TEXAS INSTRUMENTS" at 147.447,13.199 h1.52
M6 Assembly Bottom:
  lines w0.254: 10.147,21.759 177.838,21.759 ; 10.198,16.595 177.838,16.595 ; 45.91,11.265 45.91,16.417 ; 61.709,21.759 61.709,26.924 ; 83.045,21.759 83.045,26.924 ; 115.227,11.43 115.227,26.924 ; 137.808,11.43 177.825,11.43 177.825,26.924 10.147,26.924 10.147,11.43 76.111,11.43 177.838,11.43 177.838,26.924
  text "COMPONENTS MARKED 'DNP' SHOULD NOT BE POPULATED." at 172.568,32.156 h1.52
  text ".VariantName" at 146.05,29.21 h1.52
  text "ASSEMBLY VARIANT:" at 172.441,29.21 h1.52
  text ".VersionControl_RevNumber" at 43.878,23.567 h1.52
  text "SVN REV:" at 56.731,23.567 h1.52
  text ".PCB_Rev" at 70.612,23.567 h1.52
  text "REV:" at 78.016,23.567 h1.52
  text ".PRJ_Number" at 99.466,23.567 h1.52
  text "BOARD #:" at 113.322,23.567 h1.52
  text "PCB VIEWED FROM BOTTOM SIDE" at 176.225,23.567 h1.52
  text "IGNORE ->" at 82.292,18.428 h1.52
  text "TEXAS INSTRUMENTS" at 40.551,13.187 h1.52
  text ".Print_Time" at 72.669,13.187 h1.52
  text ".Print_Date" at 91.186,13.187 h1.52
  text "GENERATED    :" at 113.271,13.187 h1.52
  text ".plot_File_Name" at 155.766,13.187 h1.52
  text "PLOT NAME =" at 176.225,13.187 h1.52
M9 Title Sheet:
  drawing of 57 lines, arcs and shapes, not listed
  text "1" at 36.369,243.091 h1.78
  text "2" at 99.758,243.091 h1.78
  text "3" at 162.988,243.091 h1.78
  text "4" at 226.657,243.091 h1.78
  text "5" at 290.131,243.091 h1.78
  text "6" at 353.758,243.091 h1.78
  text "A" at 6.998,214.058 h1.78
  text "A" at 382.918,214.058 h1.78
  text "B" at 6.998,153.606 h1.78
  text "B" at 382.918,153.606 h1.78
  text ".Layer_Name" at 157.226,143.866 h1.52
  text "C" at 6.998,93.281 h1.78
  text "C" at 382.918,93.281 h1.78
  text "PROJECT TITLE:" at 305.702,46.012 h1.14
  text ".PRJ_Title" at 306.972,42.626 h1.78
  text "DESIGNED FOR:" at 305.702,38.367 h1.14
  text ".PRJ_Customer" at 306.972,34.811 h1.78
  text "D" at 6.998,33.084 h1.78
  text "D" at 382.918,33.084 h1.78
  text "FILE NAME:" at 305.702,30.747 h1.14
  text ".PCB_File_Name_No_Path" at 306.972,27.699 h1.78
  text "Texas Instruments (TI) and/or its licensors do not warrant the accuracy or completeness of this specification" at 179.476,23.588 h1.14
  text "ENGINEER:" at 305.702,23.381 h1.14
  text "LAYOUT BY:" at 343.929,23.381 h1.14
  text "or any information contained therein. TI and/or its licensors do not warrant that this design will meet" at 178.334,20.726 h1.14
  text ".PRJ_Engineer" at 306.972,19.444 h1.78
  text ".PCB_Layout" at 345.211,19.444 h1.78
  text "the specifications, will be suitable for your application or fit for any particular purpose, or will operate in" at 178.334,17.865 h1.14
  text "ALTIUM DESIGNER VERSION:" at 343.929,15.507 h1.14
  text "an implementation. TI and/or its licensors do not warrant that the design is production worthy. You should" at 178.334,15.003 h1.14
  text "completely validate and test your design implementation to confirm the system functionality for your application." at 179.476,12.141 h1.14
  text ".print_Scale" at 306.972,12.12 h1.78
  text ".Application_BuildNumber" at 345.211,12.12 h1.78
  text "1" at 36.369,6.871 h1.78
  text "2" at 99.758,6.871 h1.78
  text "3" at 162.988,6.871 h1.78
  text "4" at 226.657,6.871 h1.78
  text "5" at 290.131,6.871 h1.78
  text "6" at 353.758,6.871 h1.78
M10 Fab Notes:
  drawing of 185 lines, arcs and shapes, not listed
  text "DESIGN INFORMATION" at 332.055,190.348 h1.52
  text "MIN. TRACK WIDTH:" at 315.683,185.776 h1.52
  text "8" at 343.527,185.776 h1.52
  text "MIL" at 347.458,185.776 h1.52
  text "MIN. CLEARANCE:" at 315.683,182.423 h1.52
  text "0.2" at 342.003,182.423 h1.52
  text "mm" at 347.458,182.423 h1.52
  text "MIN. VIA PAD SIZE:" at 315.683,179.07 h1.52
  text "24" at 342.766,179.07 h1.52
  text "MIL" at 347.458,179.07 h1.52
  text "0.05mm (2MIL)" at 333.336,175.471 h1.52
  text "MINIMUM ANNULAR RING" at 307.32,175.362 h1.52
  text "EXTERNAL" at 351.319,175.362 h1.52
  text "PER" at 312.4,172.364 h1.52
  text "IPC-D-275 CLASS 2 LEVEL C" at 317.988,172.364 h1.52
  text "MIL, HOLES" at 355.789,169.512 h1.52
  text "+/-" at 345.821,169.494 h1.52
  text "+/-" at 367.513,169.494 h1.52
  text "REGISTRATION TOLERANCES:" at 307.32,169.367 h1.52
  text "METAL" at 337.795,169.367 h1.52
  text "5" at 352.43,169.367 h1.52
  text "3" at 373.588,169.367 h1.52
  text "MIL" at 376.541,169.367 h1.52
  text "MATERIAL:" at 305.421,164.047 h1.52
  text "FR-4 High Tg" at 330.477,160.482 h1.52
  text "FR-408" at 316.115,160.265 h1.52
  text "X" at 326.579,160.265 h1.52
  text "OTHER" at 353.91,160.265 h1.52
  text "62 MIL (1.6mm) +/-10%" at 324.245,156.132 h1.52
  text "THICKNESS:" at 307.32,156.023 h1.52
  text "X" at 320.99,156.023 h1.52
  text "OTHER" at 356.882,156.023 h1.52
  text "TOLERANCE:" at 307.32,152.01 h1.52
  text "X" at 328.639,152.01 h1.52
  text "ANSI IPC-6012 TYPE 3 CLASS 2" at 333.387,152.01 h1.52
  text "OTHER +/-" at 333.387,148.047 h1.52
  text "BOW & TWIST:" at 307.32,144.06 h1.52
  text "X" at 328.639,144.06 h1.52
  text "ANSI IPC-6012 TYPE 3 CLASS 2" at 333.387,144.06 h1.52
  text ".Layer_Name" at 157.226,141.326 h1.52
  text "OTHER +/-" at 333.387,140.034 h1.52
  text "DRILLING:" at 305.421,136.516 h1.52
  text "REFERENCE:" at 307.32,133.544 h1.52
  text "X" at 323.785,133.544 h1.52
  text "AS SHOWN" at 328.535,133.544 h1.52
  text "X" at 346.671,133.544 h1.52
  text "NC_DRILL FILES" at 350.151,133.544 h1.52
  text "PTH MIN COPPER THICKNESS:" at 307.32,129.531 h1.52
  text "X" at 341.616,129.531 h1.52
  text "1MIL" at 345.096,129.531 h1.52
  text "OTHER" at 357.72,129.531 h1.52
  text "BOARD FINISH:" at 305.421,125.492 h1.52
  text "SILKSCREEN:" at 309.364,122.495 h1.52
  text "X" at 333.463,122.495 h1.52
  text "TOP" at 336.663,122.495 h1.52
  text "X" at 346.417,122.495 h1.52
  text "BOTTOM" at 349.643,122.495 h1.52
  text "SILKSCREEN COLOR:" at 310.634,118.26 h1.52
  text "X" at 333.436,118.253 h1.52
  text "WHITE" at 336.663,118.253 h1.52
  text "OTHER" at 349.643,118.253 h1.52
  text "SOLDER RESIST COLOR:" at 309.364,113.935 h1.52
  text "GREEN" at 327.011,109.892 h1.52
  text "BLUE" at 342.023,109.892 h1.52
  text "OTHER" at 355.688,109.892 h1.52
  text "X" at 323.785,109.644 h1.52
  text "IMMERSION GOLD (ENIG)" at 332.371,105.103 h1.52
  text "ENEPIG" at 366.344,105.02 h1.52
  text "SURFACE FINISH:" at 305.421,104.994 h1.52
  text "X" at 327.622,104.994 h1.52
  text "IMM. TIN/SILVER OR EQUIV" at 313.792,101.007 h1.52
  text "OTHER" at 350.151,101.007 h1.52
  text "ARRAY/PANEL:" at 305.421,96.46 h1.52
  text "CUT AND TRIM PER MECH LAYER 1" at 332.371,96.351 h1.52
  text "N.C. ROUTE" at 332.371,92.498 h1.52
  text "X" at 349.617,92.498 h1.52
  text "V. SCORE" at 354.367,92.498 h1.52
  text "CERTIFICATION:" at 305.421,89.018 h1.52
  text "MATERIALS AND WORKMANSHIP FOR ALL PCBS" at 323.836,89.018 h1.52
  text "TO MEET OR EXCEED THE REQUIREMENTS OF:" at 323.836,86.529 h1.52
  text "X" at 314.349,83.061 h1.52
  text "ANSI IPC-A-600F CLASS ->" at 317.88,83.061 h1.52
  text "X" at 359.512,83.061 h1.52
  text "2" at 362.533,83.061 h1.52
  text "1" at 354.532,83.023 h1.52
  text "3" at 371.525,83.023 h1.52
  text "X" at 314.402,79.01 h1.52
  text "UL 94V-0" at 317.88,79.01 h1.52
  text "X" at 335.026,79.01 h1.52
  text "RoHS" at 338.505,79.01 h1.52
  text "OTHER" at 354.873,79.01 h1.52
  text "PER ORDER" at 364.958,79.01 h1.52
  text "ADDITIONAL REQUIREMENTS:" at 305.193,75.302 h1.52
  text "MICROSECTION:" at 307.092,72.381 h1.52
  text "YES" at 330.098,72.381 h1.52
  text "REQUIRED" at 352.208,68.542 h1.52
  text "NONE" at 340.486,68.469 h1.52
  text "X" at 348.982,68.469 h1.52
  text "PER ORDER" at 367.245,68.469 h1.52
  text "BARE BOARD ELEC. TEST:" at 307.092,68.342 h1.52
  text "MANUFACTURER'S UL:" at 307.092,64.354 h1.52
  text "METAL" at 349.422,64.373 h1.52
  text "X" at 358.953,64.364 h1.52
  text "SILK" at 362.419,64.373 h1.52
  text "RAIL" at 336.702,64.245 h1.52
M11 Gerber Information:
  lines w0.254: 10.16,16.607 177.8,16.607 ; 10.16,21.772 177.851,21.772 ; 10.16,26.937 10.16,11.443 111.887,11.443 177.851,11.443 177.851,26.937 10.173,26.937 10.173,11.443 50.19,11.443 ; 72.771,11.443 72.771,26.937 ; 104.953,21.772 104.953,26.937 ; 126.289,21.772 126.289,26.937 ; 142.088,11.278 142.088,16.43
  text "ALL ARTWORK VIEWED FROM TOP SIDE" at 11.773,23.58 h1.52
  text "BOARD #:" at 74.676,23.58 h1.52
  text ".PRJ_Number" at 88.532,23.58 h1.52
  text "REV:" at 109.982,23.58 h1.52
  text ".PCB_Rev" at 117.386,23.58 h1.52
  text "SVN REV:" at 131.267,23.58 h1.52
  text ".VersionControl_RevNumber" at 144.12,23.58 h1.52
  text "LAYER NAME =" at 11.773,18.428 h1.52
  text "PLOT NAME =" at 11.773,13.199 h1.52
  text ".plot_File_Name" at 32.233,13.199 h1.52
  text "GENERATED    :" at 74.727,13.199 h1.52
  text ".Print_Date" at 96.812,13.199 h1.52
  text ".Print_Time" at 115.329,13.199 h1.52
  text "TEXAS INSTRUMENTS" at 147.447,13.199 h1.52
M12 Stackup:
  lines w0.152: 305.105,221.59 369.875,221.59 ; 305.105,224.241 369.875,224.241 ; 303.581,209.271 ccw(c304.444,209.271) 304.444,208.407 370.535,208.407 ccw(c370.535,209.271) 371.399,209.271 371.399,227.203 ccw(c370.535,227.203) 370.535,228.067 304.444,228.067 ccw(c304.444,227.203) 303.581,227.203 303.581,209.271
  text "The Stackup Legend below this is static." at 311.34,232.118 h1.52
  text "If you change the stackup, update the Legend." at 311.594,229.832 h1.52
  text "Layer Stack Up Detail for: Ref_Design.PcbDoc" at 305.105,225.072 h1.45
  text "Layer" at 305.105,223.251 h0.61
  text "Gerber" at 327.858,223.251 h0.61
  text "Copper" at 342.172,223.251 h0.61
  text "Dielectric" at 357.481,223.251 h0.61
  text "Name" at 305.105,222.032 h0.61
  text "Document" at 327.858,222.032 h0.61
  text "Thickness" at 342.172,222.032 h0.61
  text "Material" at 357.481,222.032 h0.61
  text "Top Solder Mask" at 305.105,219.67 h0.86
  text "(.GTS)" at 327.858,219.67 h0.86
  text "Solder Resist" at 357.481,219.67 h0.86
  text ".Layer_Name" at 284.988,218.186 h1.52
  text "Top Layer" at 305.105,217.213 h0.86
  text "(.GTL)" at 327.858,217.213 h0.86
  text "1.4mil" at 342.172,217.213 h0.86
  text "FR-4" at 357.481,215.984 h0.86
  text "Bottom Layer" at 305.105,214.755 h0.86
  text "(.GBL)" at 327.858,214.755 h0.86
  text "1.4mil" at 342.172,214.755 h0.86
  text "Bottom Solder Mask" at 305.105,212.298 h0.86
  text "(.GBS)" at 327.858,212.298 h0.86
  text "Solder Resist" at 357.481,212.298 h0.86
M13 Component Bodies Top:
  text ".Layer_Name" at 157.226,138.786 h1.52
M14 Component Bodies Bottom:
  text ".Layer_Name" at 157.226,136.246 h1.52
M15 Courtyards Top:
  text ".Layer_Name" at 157.226,133.706 h1.52
M16 Courtyards Bottom:
  text ".Layer_Name" at 157.226,131.166 h1.52
Drill Drawing:
  text ".Layer_Name" at 157.226,105.766 h1.52

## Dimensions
145.263,143.358 to 151.917,158.471 on M2 Board Dimensions
28.829,143.358 to 20.218,169.037 on M2 Board Dimensions
125.832,61.646 to 151.917,58.649 on M2 Board Dimensions
20.218,58.649 to 49.124,60.96 on M2 Board Dimensions
133.833,143.358 to 145.263,143.358 on M2 Board Dimensions
28.829,143.358 to 40.259,143.358 on M2 Board Dimensions
17.577,29.807 to 42.977,29.807 on M2 Board Dimensions
75.997,72.492 to 99.365,72.492 on M2 Board Dimensions
99.365,97.13 to 99.365,72.492 on M2 Board Dimensions
99.873,71.984 to 125.832,61.646 on M2 Board Dimensions
49.124,60.96 to 75.438,71.984 on M2 Board Dimensions
49.124,60.96 to 125.832,61.646 on M2 Board Dimensions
